VERSION 5.7 ;
  NOWIREEXTENSIONATPIN ON ;
  DIVIDERCHAR "/" ;
  BUSBITCHARS "[]" ;
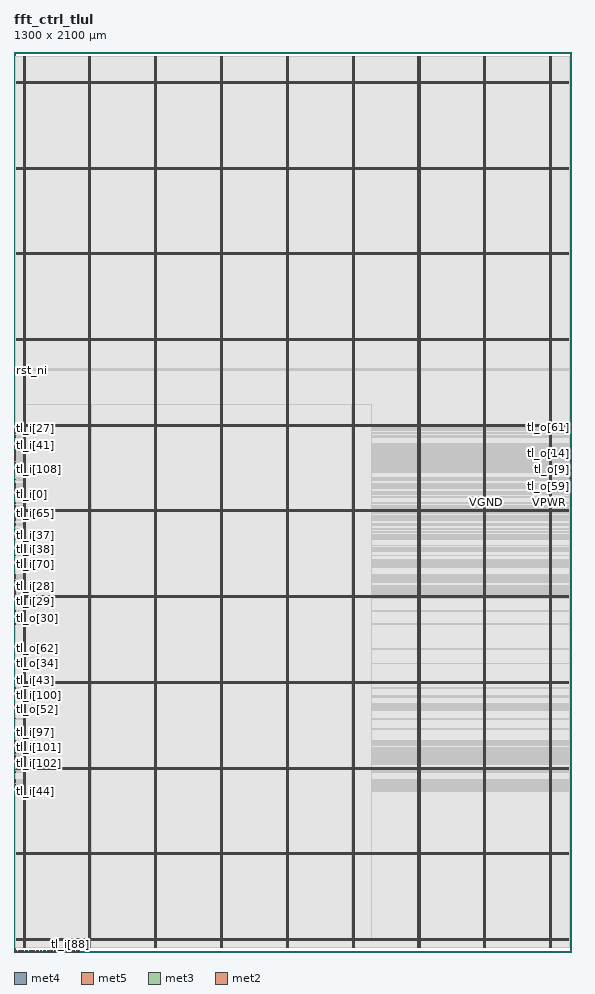
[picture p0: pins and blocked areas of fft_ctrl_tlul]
MACRO fft_ctrl_tlul
  CLASS BLOCK ;
  FOREIGN fft_ctrl_tlul ;
  ORIGIN 0.000 0.000 ;
  SIZE 1300.000 BY 2100.000 ;
  PIN VGND
    DIRECTION INOUT ;
    USE GROUND ;
    PORT
      LAYER met4 ;
        RECT 24.340 10.640 25.940 2089.200 ;
    END
    PORT
      LAYER met4 ;
        RECT 177.940 10.640 179.540 2089.200 ;
    END
    PORT
      LAYER met4 ;
        RECT 331.540 10.640 333.140 2089.200 ;
    END
    PORT
      LAYER met4 ;
        RECT 485.140 10.640 486.740 2089.200 ;
    END
    PORT
      LAYER met4 ;
        RECT 638.740 10.640 640.340 2089.200 ;
    END
    PORT
      LAYER met4 ;
        RECT 792.340 10.640 793.940 2089.200 ;
    END
    PORT
      LAYER met4 ;
        RECT 945.940 10.640 947.540 2089.200 ;
    END
    PORT
      LAYER met4 ;
        RECT 1099.540 10.640 1101.140 2089.200 ;
    END
    PORT
      LAYER met4 ;
        RECT 1253.140 10.640 1254.740 2089.200 ;
    END
    PORT
      LAYER met5 ;
        RECT 5.280 30.030 1294.680 31.630 ;
    END
    PORT
      LAYER met5 ;
        RECT 5.280 230.030 1294.680 231.630 ;
    END
    PORT
      LAYER met5 ;
        RECT 5.280 430.030 1294.680 431.630 ;
    END
    PORT
      LAYER met5 ;
        RECT 5.280 630.030 1294.680 631.630 ;
    END
    PORT
      LAYER met5 ;
        RECT 5.280 830.030 1294.680 831.630 ;
    END
    PORT
      LAYER met5 ;
        RECT 5.280 1030.030 1294.680 1031.630 ;
    END
    PORT
      LAYER met5 ;
        RECT 5.280 1230.030 1294.680 1231.630 ;
    END
    PORT
      LAYER met5 ;
        RECT 5.280 1430.030 1294.680 1431.630 ;
    END
    PORT
      LAYER met5 ;
        RECT 5.280 1630.030 1294.680 1631.630 ;
    END
    PORT
      LAYER met5 ;
        RECT 5.280 1830.030 1294.680 1831.630 ;
    END
    PORT
      LAYER met5 ;
        RECT 5.280 2030.030 1294.680 2031.630 ;
    END
  END VGND
  PIN VPWR
    DIRECTION INOUT ;
    USE POWER ;
    PORT
      LAYER met4 ;
        RECT 21.040 10.640 22.640 2089.200 ;
    END
    PORT
      LAYER met4 ;
        RECT 174.640 10.640 176.240 2089.200 ;
    END
    PORT
      LAYER met4 ;
        RECT 328.240 10.640 329.840 2089.200 ;
    END
    PORT
      LAYER met4 ;
        RECT 481.840 10.640 483.440 2089.200 ;
    END
    PORT
      LAYER met4 ;
        RECT 635.440 10.640 637.040 2089.200 ;
    END
    PORT
      LAYER met4 ;
        RECT 789.040 10.640 790.640 2089.200 ;
    END
    PORT
      LAYER met4 ;
        RECT 942.640 10.640 944.240 2089.200 ;
    END
    PORT
      LAYER met4 ;
        RECT 1096.240 10.640 1097.840 2089.200 ;
    END
    PORT
      LAYER met4 ;
        RECT 1249.840 10.640 1251.440 2089.200 ;
    END
    PORT
      LAYER met5 ;
        RECT 5.280 26.730 1294.680 28.330 ;
    END
    PORT
      LAYER met5 ;
        RECT 5.280 226.730 1294.680 228.330 ;
    END
    PORT
      LAYER met5 ;
        RECT 5.280 426.730 1294.680 428.330 ;
    END
    PORT
      LAYER met5 ;
        RECT 5.280 626.730 1294.680 628.330 ;
    END
    PORT
      LAYER met5 ;
        RECT 5.280 826.730 1294.680 828.330 ;
    END
    PORT
      LAYER met5 ;
        RECT 5.280 1026.730 1294.680 1028.330 ;
    END
    PORT
      LAYER met5 ;
        RECT 5.280 1226.730 1294.680 1228.330 ;
    END
    PORT
      LAYER met5 ;
        RECT 5.280 1426.730 1294.680 1428.330 ;
    END
    PORT
      LAYER met5 ;
        RECT 5.280 1626.730 1294.680 1628.330 ;
    END
    PORT
      LAYER met5 ;
        RECT 5.280 1826.730 1294.680 1828.330 ;
    END
    PORT
      LAYER met5 ;
        RECT 5.280 2026.730 1294.680 2028.330 ;
    END
  END VPWR
  PIN clk_i
    DIRECTION INPUT ;
    USE SIGNAL ;
    ANTENNAGATEAREA 0.929700 ;
    ANTENNADIFFAREA 0.434700 ;
    PORT
      LAYER met3 ;
        RECT 0.000 1360.040 4.000 1360.640 ;
    END
  END clk_i
  PIN fft_done_o
    DIRECTION OUTPUT ;
    USE SIGNAL ;
    ANTENNADIFFAREA 0.445500 ;
    PORT
      LAYER met3 ;
        RECT 0.000 1088.040 4.000 1088.640 ;
    END
  END fft_done_o
  PIN fft_error_o
    DIRECTION OUTPUT ;
    USE SIGNAL ;
    ANTENNADIFFAREA 0.445500 ;
    PORT
      LAYER met3 ;
        RECT 0.000 1060.840 4.000 1061.440 ;
    END
  END fft_error_o
  PIN rst_ni
    DIRECTION INPUT ;
    USE SIGNAL ;
    ANTENNAGATEAREA 0.631200 ;
    ANTENNADIFFAREA 0.434700 ;
    PORT
      LAYER met3 ;
        RECT 0.000 1356.640 4.000 1357.240 ;
    END
  END rst_ni
  PIN tl_i[0]
    DIRECTION INPUT ;
    USE SIGNAL ;
    ANTENNAGATEAREA 0.631200 ;
    ANTENNADIFFAREA 0.434700 ;
    PORT
      LAYER met3 ;
        RECT 0.000 1067.640 4.000 1068.240 ;
    END
  END tl_i[0]
  PIN tl_i[100]
    DIRECTION INPUT ;
    USE SIGNAL ;
    ANTENNAGATEAREA 0.631200 ;
    ANTENNADIFFAREA 0.434700 ;
    PORT
      LAYER met3 ;
        RECT 0.000 598.440 4.000 599.040 ;
    END
  END tl_i[100]
  PIN tl_i[101]
    DIRECTION INPUT ;
    USE SIGNAL ;
    ANTENNAGATEAREA 0.631200 ;
    ANTENNADIFFAREA 0.434700 ;
    PORT
      LAYER met3 ;
        RECT 0.000 476.040 4.000 476.640 ;
    END
  END tl_i[101]
  PIN tl_i[102]
    DIRECTION INPUT ;
    USE SIGNAL ;
    ANTENNAGATEAREA 0.631200 ;
    ANTENNADIFFAREA 0.434700 ;
    PORT
      LAYER met3 ;
        RECT 0.000 459.040 4.000 459.640 ;
    END
  END tl_i[102]
  PIN tl_i[103]
    DIRECTION INPUT ;
    USE SIGNAL ;
    PORT
      LAYER met2 ;
        RECT 0.090 0.000 0.370 4.000 ;
    END
  END tl_i[103]
  PIN tl_i[104]
    DIRECTION INPUT ;
    USE SIGNAL ;
    PORT
      LAYER met2 ;
        RECT 3.310 0.000 3.590 4.000 ;
    END
  END tl_i[104]
  PIN tl_i[105]
    DIRECTION INPUT ;
    USE SIGNAL ;
    PORT
      LAYER met2 ;
        RECT 6.530 0.000 6.810 4.000 ;
    END
  END tl_i[105]
  PIN tl_i[106]
    DIRECTION INPUT ;
    USE SIGNAL ;
    PORT
      LAYER met2 ;
        RECT 9.750 0.000 10.030 4.000 ;
    END
  END tl_i[106]
  PIN tl_i[107]
    DIRECTION INPUT ;
    USE SIGNAL ;
    ANTENNAGATEAREA 0.631200 ;
    ANTENNADIFFAREA 0.434700 ;
    PORT
      LAYER met3 ;
        RECT 0.000 1122.040 4.000 1122.640 ;
    END
  END tl_i[107]
  PIN tl_i[108]
    DIRECTION INPUT ;
    USE SIGNAL ;
    ANTENNAGATEAREA 0.631200 ;
    ANTENNADIFFAREA 0.434700 ;
    PORT
      LAYER met3 ;
        RECT 0.000 1125.440 4.000 1126.040 ;
    END
  END tl_i[108]
  PIN tl_i[109]
    DIRECTION INPUT ;
    USE SIGNAL ;
    ANTENNAGATEAREA 0.631200 ;
    ANTENNADIFFAREA 0.434700 ;
    PORT
      LAYER met3 ;
        RECT 0.000 1074.440 4.000 1075.040 ;
    END
  END tl_i[109]
  PIN tl_i[10]
    DIRECTION INPUT ;
    USE SIGNAL ;
    PORT
      LAYER met2 ;
        RECT 12.970 0.000 13.250 4.000 ;
    END
  END tl_i[10]
  PIN tl_i[11]
    DIRECTION INPUT ;
    USE SIGNAL ;
    PORT
      LAYER met2 ;
        RECT 16.190 0.000 16.470 4.000 ;
    END
  END tl_i[11]
  PIN tl_i[12]
    DIRECTION INPUT ;
    USE SIGNAL ;
    PORT
      LAYER met2 ;
        RECT 19.410 0.000 19.690 4.000 ;
    END
  END tl_i[12]
  PIN tl_i[13]
    DIRECTION INPUT ;
    USE SIGNAL ;
    PORT
      LAYER met2 ;
        RECT 22.630 0.000 22.910 4.000 ;
    END
  END tl_i[13]
  PIN tl_i[14]
    DIRECTION INPUT ;
    USE SIGNAL ;
    PORT
      LAYER met2 ;
        RECT 25.850 0.000 26.130 4.000 ;
    END
  END tl_i[14]
  PIN tl_i[15]
    DIRECTION INPUT ;
    USE SIGNAL ;
    PORT
      LAYER met2 ;
        RECT 29.070 0.000 29.350 4.000 ;
    END
  END tl_i[15]
  PIN tl_i[16]
    DIRECTION INPUT ;
    USE SIGNAL ;
    PORT
      LAYER met2 ;
        RECT 32.290 0.000 32.570 4.000 ;
    END
  END tl_i[16]
  PIN tl_i[17]
    DIRECTION INPUT ;
    USE SIGNAL ;
    PORT
      LAYER met2 ;
        RECT 35.510 0.000 35.790 4.000 ;
    END
  END tl_i[17]
  PIN tl_i[18]
    DIRECTION INPUT ;
    USE SIGNAL ;
    PORT
      LAYER met2 ;
        RECT 38.730 0.000 39.010 4.000 ;
    END
  END tl_i[18]
  PIN tl_i[19]
    DIRECTION INPUT ;
    USE SIGNAL ;
    PORT
      LAYER met2 ;
        RECT 41.950 0.000 42.230 4.000 ;
    END
  END tl_i[19]
  PIN tl_i[1]
    DIRECTION INPUT ;
    USE SIGNAL ;
    PORT
      LAYER met2 ;
        RECT 45.170 0.000 45.450 4.000 ;
    END
  END tl_i[1]
  PIN tl_i[20]
    DIRECTION INPUT ;
    USE SIGNAL ;
    PORT
      LAYER met2 ;
        RECT 48.390 0.000 48.670 4.000 ;
    END
  END tl_i[20]
  PIN tl_i[21]
    DIRECTION INPUT ;
    USE SIGNAL ;
    PORT
      LAYER met2 ;
        RECT 51.610 0.000 51.890 4.000 ;
    END
  END tl_i[21]
  PIN tl_i[22]
    DIRECTION INPUT ;
    USE SIGNAL ;
    PORT
      LAYER met2 ;
        RECT 54.830 0.000 55.110 4.000 ;
    END
  END tl_i[22]
  PIN tl_i[23]
    DIRECTION INPUT ;
    USE SIGNAL ;
    PORT
      LAYER met2 ;
        RECT 58.050 0.000 58.330 4.000 ;
    END
  END tl_i[23]
  PIN tl_i[24]
    DIRECTION INPUT ;
    USE SIGNAL ;
    PORT
      LAYER met2 ;
        RECT 61.270 0.000 61.550 4.000 ;
    END
  END tl_i[24]
  PIN tl_i[25]
    DIRECTION INPUT ;
    USE SIGNAL ;
    ANTENNAGATEAREA 0.631200 ;
    ANTENNADIFFAREA 0.434700 ;
    PORT
      LAYER met3 ;
        RECT 0.000 1162.840 4.000 1163.440 ;
    END
  END tl_i[25]
  PIN tl_i[26]
    DIRECTION INPUT ;
    USE SIGNAL ;
    ANTENNAGATEAREA 0.631200 ;
    ANTENNADIFFAREA 0.434700 ;
    PORT
      LAYER met3 ;
        RECT 0.000 833.040 4.000 833.640 ;
    END
  END tl_i[26]
  PIN tl_i[27]
    DIRECTION INPUT ;
    USE SIGNAL ;
    ANTENNAGATEAREA 0.631200 ;
    ANTENNADIFFAREA 0.434700 ;
    PORT
      LAYER met3 ;
        RECT 0.000 1220.640 4.000 1221.240 ;
    END
  END tl_i[27]
  PIN tl_i[28]
    DIRECTION INPUT ;
    USE SIGNAL ;
    ANTENNAGATEAREA 0.631200 ;
    ANTENNADIFFAREA 0.434700 ;
    PORT
      LAYER met3 ;
        RECT 0.000 853.440 4.000 854.040 ;
    END
  END tl_i[28]
  PIN tl_i[29]
    DIRECTION INPUT ;
    USE SIGNAL ;
    ANTENNAGATEAREA 0.631200 ;
    ANTENNADIFFAREA 0.434700 ;
    PORT
      LAYER met3 ;
        RECT 0.000 836.440 4.000 837.040 ;
    END
  END tl_i[29]
  PIN tl_i[2]
    DIRECTION INPUT ;
    USE SIGNAL ;
    PORT
      LAYER met2 ;
        RECT 64.490 0.000 64.770 4.000 ;
    END
  END tl_i[2]
  PIN tl_i[30]
    DIRECTION INPUT ;
    USE SIGNAL ;
    ANTENNAGATEAREA 0.631200 ;
    ANTENNADIFFAREA 0.434700 ;
    PORT
      LAYER met3 ;
        RECT 0.000 1217.240 4.000 1217.840 ;
    END
  END tl_i[30]
  PIN tl_i[31]
    DIRECTION INPUT ;
    USE SIGNAL ;
    ANTENNAGATEAREA 0.631200 ;
    ANTENNADIFFAREA 0.434700 ;
    PORT
      LAYER met3 ;
        RECT 0.000 1230.840 4.000 1231.440 ;
    END
  END tl_i[31]
  PIN tl_i[32]
    DIRECTION INPUT ;
    USE SIGNAL ;
    ANTENNAGATEAREA 0.631200 ;
    ANTENNADIFFAREA 0.434700 ;
    PORT
      LAYER met3 ;
        RECT 0.000 1227.440 4.000 1228.040 ;
    END
  END tl_i[32]
  PIN tl_i[33]
    DIRECTION INPUT ;
    USE SIGNAL ;
    ANTENNAGATEAREA 0.631200 ;
    ANTENNADIFFAREA 0.434700 ;
    PORT
      LAYER met3 ;
        RECT 0.000 1210.440 4.000 1211.040 ;
    END
  END tl_i[33]
  PIN tl_i[34]
    DIRECTION INPUT ;
    USE SIGNAL ;
    ANTENNAGATEAREA 0.631200 ;
    ANTENNADIFFAREA 0.434700 ;
    PORT
      LAYER met3 ;
        RECT 0.000 914.640 4.000 915.240 ;
    END
  END tl_i[34]
  PIN tl_i[35]
    DIRECTION INPUT ;
    USE SIGNAL ;
    ANTENNAGATEAREA 0.631200 ;
    ANTENNADIFFAREA 0.434700 ;
    PORT
      LAYER met3 ;
        RECT 0.000 1224.040 4.000 1224.640 ;
    END
  END tl_i[35]
  PIN tl_i[36]
    DIRECTION INPUT ;
    USE SIGNAL ;
    ANTENNAGATEAREA 0.631200 ;
    ANTENNADIFFAREA 0.434700 ;
    PORT
      LAYER met3 ;
        RECT 0.000 826.240 4.000 826.840 ;
    END
  END tl_i[36]
  PIN tl_i[37]
    DIRECTION INPUT ;
    USE SIGNAL ;
    ANTENNAGATEAREA 0.631200 ;
    ANTENNADIFFAREA 0.434700 ;
    PORT
      LAYER met3 ;
        RECT 0.000 972.440 4.000 973.040 ;
    END
  END tl_i[37]
  PIN tl_i[38]
    DIRECTION INPUT ;
    USE SIGNAL ;
    ANTENNAGATEAREA 0.631200 ;
    ANTENNADIFFAREA 0.434700 ;
    PORT
      LAYER met3 ;
        RECT 0.000 938.440 4.000 939.040 ;
    END
  END tl_i[38]
  PIN tl_i[39]
    DIRECTION INPUT ;
    USE SIGNAL ;
    ANTENNAGATEAREA 0.631200 ;
    ANTENNADIFFAREA 0.434700 ;
    PORT
      LAYER met3 ;
        RECT 0.000 911.240 4.000 911.840 ;
    END
  END tl_i[39]
  PIN tl_i[3]
    DIRECTION INPUT ;
    USE SIGNAL ;
    PORT
      LAYER met2 ;
        RECT 67.710 0.000 67.990 4.000 ;
    END
  END tl_i[3]
  PIN tl_i[40]
    DIRECTION INPUT ;
    USE SIGNAL ;
    ANTENNAGATEAREA 0.631200 ;
    ANTENNADIFFAREA 0.434700 ;
    PORT
      LAYER met3 ;
        RECT 0.000 1139.040 4.000 1139.640 ;
    END
  END tl_i[40]
  PIN tl_i[41]
    DIRECTION INPUT ;
    USE SIGNAL ;
    ANTENNAGATEAREA 0.631200 ;
    ANTENNADIFFAREA 0.434700 ;
    PORT
      LAYER met3 ;
        RECT 0.000 1200.240 4.000 1200.840 ;
    END
  END tl_i[41]
  PIN tl_i[42]
    DIRECTION INPUT ;
    USE SIGNAL ;
    ANTENNAGATEAREA 0.631200 ;
    ANTENNADIFFAREA 0.434700 ;
    PORT
      LAYER met3 ;
        RECT 0.000 544.040 4.000 544.640 ;
    END
  END tl_i[42]
  PIN tl_i[43]
    DIRECTION INPUT ;
    USE SIGNAL ;
    ANTENNAGATEAREA 0.631200 ;
    ANTENNADIFFAREA 0.434700 ;
    PORT
      LAYER met3 ;
        RECT 0.000 615.440 4.000 616.040 ;
    END
  END tl_i[43]
  PIN tl_i[44]
    DIRECTION INPUT ;
    USE SIGNAL ;
    ANTENNAGATEAREA 0.631200 ;
    ANTENNADIFFAREA 0.434700 ;
    PORT
      LAYER met3 ;
        RECT 0.000 374.040 4.000 374.640 ;
    END
  END tl_i[44]
  PIN tl_i[45]
    DIRECTION INPUT ;
    USE SIGNAL ;
    ANTENNAGATEAREA 0.631200 ;
    ANTENNADIFFAREA 0.434700 ;
    PORT
      LAYER met3 ;
        RECT 0.000 571.240 4.000 571.840 ;
    END
  END tl_i[45]
  PIN tl_i[46]
    DIRECTION INPUT ;
    USE SIGNAL ;
    ANTENNAGATEAREA 0.631200 ;
    ANTENNADIFFAREA 0.434700 ;
    PORT
      LAYER met3 ;
        RECT 0.000 384.240 4.000 384.840 ;
    END
  END tl_i[46]
  PIN tl_i[47]
    DIRECTION INPUT ;
    USE SIGNAL ;
    ANTENNAGATEAREA 0.631200 ;
    ANTENNADIFFAREA 0.434700 ;
    PORT
      LAYER met3 ;
        RECT 0.000 401.240 4.000 401.840 ;
    END
  END tl_i[47]
  PIN tl_i[48]
    DIRECTION INPUT ;
    USE SIGNAL ;
    ANTENNAGATEAREA 0.631200 ;
    ANTENNADIFFAREA 0.434700 ;
    PORT
      LAYER met3 ;
        RECT 0.000 418.240 4.000 418.840 ;
    END
  END tl_i[48]
  PIN tl_i[49]
    DIRECTION INPUT ;
    USE SIGNAL ;
    ANTENNAGATEAREA 0.631200 ;
    ANTENNADIFFAREA 0.434700 ;
    PORT
      LAYER met3 ;
        RECT 0.000 394.440 4.000 395.040 ;
    END
  END tl_i[49]
  PIN tl_i[4]
    DIRECTION INPUT ;
    USE SIGNAL ;
    PORT
      LAYER met2 ;
        RECT 70.930 0.000 71.210 4.000 ;
    END
  END tl_i[4]
  PIN tl_i[50]
    DIRECTION INPUT ;
    USE SIGNAL ;
    ANTENNAGATEAREA 0.631200 ;
    ANTENNADIFFAREA 0.434700 ;
    PORT
      LAYER met3 ;
        RECT 0.000 397.840 4.000 398.440 ;
    END
  END tl_i[50]
  PIN tl_i[51]
    DIRECTION INPUT ;
    USE SIGNAL ;
    ANTENNAGATEAREA 0.631200 ;
    ANTENNADIFFAREA 0.434700 ;
    PORT
      LAYER met3 ;
        RECT 0.000 839.840 4.000 840.440 ;
    END
  END tl_i[51]
  PIN tl_i[52]
    DIRECTION INPUT ;
    USE SIGNAL ;
    ANTENNAGATEAREA 0.631200 ;
    ANTENNADIFFAREA 0.434700 ;
    PORT
      LAYER met3 ;
        RECT 0.000 850.040 4.000 850.640 ;
    END
  END tl_i[52]
  PIN tl_i[53]
    DIRECTION INPUT ;
    USE SIGNAL ;
    ANTENNAGATEAREA 0.631200 ;
    ANTENNADIFFAREA 0.434700 ;
    PORT
      LAYER met3 ;
        RECT 0.000 846.640 4.000 847.240 ;
    END
  END tl_i[53]
  PIN tl_i[54]
    DIRECTION INPUT ;
    USE SIGNAL ;
    ANTENNAGATEAREA 0.631200 ;
    ANTENNADIFFAREA 0.434700 ;
    PORT
      LAYER met3 ;
        RECT 0.000 880.640 4.000 881.240 ;
    END
  END tl_i[54]
  PIN tl_i[55]
    DIRECTION INPUT ;
    USE SIGNAL ;
    ANTENNAGATEAREA 0.631200 ;
    ANTENNADIFFAREA 0.434700 ;
    PORT
      LAYER met3 ;
        RECT 0.000 438.640 4.000 439.240 ;
    END
  END tl_i[55]
  PIN tl_i[56]
    DIRECTION INPUT ;
    USE SIGNAL ;
    ANTENNAGATEAREA 0.631200 ;
    ANTENNADIFFAREA 0.434700 ;
    PORT
      LAYER met3 ;
        RECT 0.000 877.240 4.000 877.840 ;
    END
  END tl_i[56]
  PIN tl_i[57]
    DIRECTION INPUT ;
    USE SIGNAL ;
    PORT
      LAYER met2 ;
        RECT 74.150 0.000 74.430 4.000 ;
    END
  END tl_i[57]
  PIN tl_i[58]
    DIRECTION INPUT ;
    USE SIGNAL ;
    PORT
      LAYER met2 ;
        RECT 77.370 0.000 77.650 4.000 ;
    END
  END tl_i[58]
  PIN tl_i[59]
    DIRECTION INPUT ;
    USE SIGNAL ;
    PORT
      LAYER met2 ;
        RECT 80.590 0.000 80.870 4.000 ;
    END
  END tl_i[59]
  PIN tl_i[5]
    DIRECTION INPUT ;
    USE SIGNAL ;
    PORT
      LAYER met2 ;
        RECT 83.810 0.000 84.090 4.000 ;
    END
  END tl_i[5]
  PIN tl_i[60]
    DIRECTION INPUT ;
    USE SIGNAL ;
    PORT
      LAYER met2 ;
        RECT 87.030 0.000 87.310 4.000 ;
    END
  END tl_i[60]
  PIN tl_i[61]
    DIRECTION INPUT ;
    USE SIGNAL ;
    ANTENNAGATEAREA 0.631200 ;
    ANTENNADIFFAREA 0.434700 ;
    PORT
      LAYER met3 ;
        RECT 0.000 986.040 4.000 986.640 ;
    END
  END tl_i[61]
  PIN tl_i[62]
    DIRECTION INPUT ;
    USE SIGNAL ;
    ANTENNAGATEAREA 0.631200 ;
    ANTENNADIFFAREA 0.434700 ;
    PORT
      LAYER met3 ;
        RECT 0.000 1009.840 4.000 1010.440 ;
    END
  END tl_i[62]
  PIN tl_i[63]
    DIRECTION INPUT ;
    USE SIGNAL ;
    ANTENNAGATEAREA 0.631200 ;
    ANTENNADIFFAREA 0.434700 ;
    PORT
      LAYER met3 ;
        RECT 0.000 935.040 4.000 935.640 ;
    END
  END tl_i[63]
  PIN tl_i[64]
    DIRECTION INPUT ;
    USE SIGNAL ;
    ANTENNAGATEAREA 0.631200 ;
    ANTENNADIFFAREA 0.434700 ;
    PORT
      LAYER met3 ;
        RECT 0.000 996.240 4.000 996.840 ;
    END
  END tl_i[64]
  PIN tl_i[65]
    DIRECTION INPUT ;
    USE SIGNAL ;
    ANTENNAGATEAREA 0.631200 ;
    ANTENNADIFFAREA 0.434700 ;
    PORT
      LAYER met3 ;
        RECT 0.000 1023.440 4.000 1024.040 ;
    END
  END tl_i[65]
  PIN tl_i[66]
    DIRECTION INPUT ;
    USE SIGNAL ;
    ANTENNAGATEAREA 0.631200 ;
    ANTENNADIFFAREA 0.434700 ;
    PORT
      LAYER met3 ;
        RECT 0.000 1030.240 4.000 1030.840 ;
    END
  END tl_i[66]
  PIN tl_i[67]
    DIRECTION INPUT ;
    USE SIGNAL ;
    ANTENNAGATEAREA 0.631200 ;
    ANTENNADIFFAREA 0.434700 ;
    PORT
      LAYER met3 ;
        RECT 0.000 965.640 4.000 966.240 ;
    END
  END tl_i[67]
  PIN tl_i[68]
    DIRECTION INPUT ;
    USE SIGNAL ;
    ANTENNAGATEAREA 0.631200 ;
    ANTENNADIFFAREA 0.434700 ;
    PORT
      LAYER met3 ;
        RECT 0.000 863.640 4.000 864.240 ;
    END
  END tl_i[68]
  PIN tl_i[69]
    DIRECTION INPUT ;
    USE SIGNAL ;
    ANTENNAGATEAREA 0.631200 ;
    ANTENNADIFFAREA 0.434700 ;
    PORT
      LAYER met3 ;
        RECT 0.000 843.240 4.000 843.840 ;
    END
  END tl_i[69]
  PIN tl_i[6]
    DIRECTION INPUT ;
    USE SIGNAL ;
    PORT
      LAYER met2 ;
        RECT 90.250 0.000 90.530 4.000 ;
    END
  END tl_i[6]
  PIN tl_i[70]
    DIRECTION INPUT ;
    USE SIGNAL ;
    ANTENNAGATEAREA 0.631200 ;
    ANTENNADIFFAREA 0.434700 ;
    PORT
      LAYER met3 ;
        RECT 0.000 904.440 4.000 905.040 ;
    END
  END tl_i[70]
  PIN tl_i[71]
    DIRECTION INPUT ;
    USE SIGNAL ;
    ANTENNAGATEAREA 0.631200 ;
    ANTENNADIFFAREA 0.434700 ;
    PORT
      LAYER met3 ;
        RECT 0.000 870.440 4.000 871.040 ;
    END
  END tl_i[71]
  PIN tl_i[72]
    DIRECTION INPUT ;
    USE SIGNAL ;
    ANTENNAGATEAREA 0.631200 ;
    ANTENNADIFFAREA 0.434700 ;
    PORT
      LAYER met3 ;
        RECT 0.000 948.640 4.000 949.240 ;
    END
  END tl_i[72]
  PIN tl_i[73]
    DIRECTION INPUT ;
    USE SIGNAL ;
    ANTENNAGATEAREA 0.631200 ;
    ANTENNADIFFAREA 0.434700 ;
    PORT
      LAYER met3 ;
        RECT 0.000 1145.840 4.000 1146.440 ;
    END
  END tl_i[73]
  PIN tl_i[74]
    DIRECTION INPUT ;
    USE SIGNAL ;
    ANTENNAGATEAREA 0.631200 ;
    ANTENNADIFFAREA 0.434700 ;
    PORT
      LAYER met3 ;
        RECT 0.000 1176.440 4.000 1177.040 ;
    END
  END tl_i[74]
  PIN tl_i[75]
    DIRECTION INPUT ;
    USE SIGNAL ;
    ANTENNAGATEAREA 0.631200 ;
    ANTENNADIFFAREA 0.434700 ;
    PORT
      LAYER met3 ;
        RECT 0.000 1166.240 4.000 1166.840 ;
    END
  END tl_i[75]
  PIN tl_i[76]
    DIRECTION INPUT ;
    USE SIGNAL ;
    ANTENNAGATEAREA 0.631200 ;
    ANTENNADIFFAREA 0.434700 ;
    PORT
      LAYER met3 ;
        RECT 0.000 1152.640 4.000 1153.240 ;
    END
  END tl_i[76]
  PIN tl_i[77]
    DIRECTION INPUT ;
    USE SIGNAL ;
    PORT
      LAYER met2 ;
        RECT 93.470 0.000 93.750 4.000 ;
    END
  END tl_i[77]
  PIN tl_i[78]
    DIRECTION INPUT ;
    USE SIGNAL ;
    PORT
      LAYER met2 ;
        RECT 96.690 0.000 96.970 4.000 ;
    END
  END tl_i[78]
  PIN tl_i[79]
    DIRECTION INPUT ;
    USE SIGNAL ;
    PORT
      LAYER met2 ;
        RECT 99.910 0.000 100.190 4.000 ;
    END
  END tl_i[79]
  PIN tl_i[7]
    DIRECTION INPUT ;
    USE SIGNAL ;
    PORT
      LAYER met2 ;
        RECT 103.130 0.000 103.410 4.000 ;
    END
  END tl_i[7]
  PIN tl_i[80]
    DIRECTION INPUT ;
    USE SIGNAL ;
    PORT
      LAYER met2 ;
        RECT 106.350 0.000 106.630 4.000 ;
    END
  END tl_i[80]
  PIN tl_i[81]
    DIRECTION INPUT ;
    USE SIGNAL ;
    PORT
      LAYER met2 ;
        RECT 109.570 0.000 109.850 4.000 ;
    END
  END tl_i[81]
  PIN tl_i[82]
    DIRECTION INPUT ;
    USE SIGNAL ;
    PORT
      LAYER met2 ;
        RECT 112.790 0.000 113.070 4.000 ;
    END
  END tl_i[82]
  PIN tl_i[83]
    DIRECTION INPUT ;
    USE SIGNAL ;
    PORT
      LAYER met2 ;
        RECT 116.010 0.000 116.290 4.000 ;
    END
  END tl_i[83]
  PIN tl_i[84]
    DIRECTION INPUT ;
    USE SIGNAL ;
    PORT
      LAYER met2 ;
        RECT 119.230 0.000 119.510 4.000 ;
    END
  END tl_i[84]
  PIN tl_i[85]
    DIRECTION INPUT ;
    USE SIGNAL ;
    PORT
      LAYER met2 ;
        RECT 122.450 0.000 122.730 4.000 ;
    END
  END tl_i[85]
  PIN tl_i[86]
    DIRECTION INPUT ;
    USE SIGNAL ;
    PORT
      LAYER met2 ;
        RECT 125.670 0.000 125.950 4.000 ;
    END
  END tl_i[86]
  PIN tl_i[87]
    DIRECTION INPUT ;
    USE SIGNAL ;
    PORT
      LAYER met2 ;
        RECT 128.890 0.000 129.170 4.000 ;
    END
  END tl_i[87]
  PIN tl_i[88]
    DIRECTION INPUT ;
    USE SIGNAL ;
    PORT
      LAYER met2 ;
        RECT 132.110 0.000 132.390 4.000 ;
    END
  END tl_i[88]
  PIN tl_i[89]
    DIRECTION INPUT ;
    USE SIGNAL ;
    PORT
      LAYER met2 ;
        RECT 135.330 0.000 135.610 4.000 ;
    END
  END tl_i[89]
  PIN tl_i[8]
    DIRECTION INPUT ;
    USE SIGNAL ;
    PORT
      LAYER met2 ;
        RECT 138.550 0.000 138.830 4.000 ;
    END
  END tl_i[8]
  PIN tl_i[90]
    DIRECTION INPUT ;
    USE SIGNAL ;
    PORT
      LAYER met2 ;
        RECT 141.770 0.000 142.050 4.000 ;
    END
  END tl_i[90]
  PIN tl_i[91]
    DIRECTION INPUT ;
    USE SIGNAL ;
    PORT
      LAYER met2 ;
        RECT 144.990 0.000 145.270 4.000 ;
    END
  END tl_i[91]
  PIN tl_i[92]
    DIRECTION INPUT ;
    USE SIGNAL ;
    PORT
      LAYER met2 ;
        RECT 148.210 0.000 148.490 4.000 ;
    END
  END tl_i[92]
  PIN tl_i[93]
    DIRECTION INPUT ;
    USE SIGNAL ;
    ANTENNAGATEAREA 0.631200 ;
    ANTENNADIFFAREA 0.434700 ;
    PORT
      LAYER met3 ;
        RECT 0.000 380.840 4.000 381.440 ;
    END
  END tl_i[93]
  PIN tl_i[94]
    DIRECTION INPUT ;
    USE SIGNAL ;
    ANTENNAGATEAREA 0.631200 ;
    ANTENNADIFFAREA 0.434700 ;
    PORT
      LAYER met3 ;
        RECT 0.000 391.040 4.000 391.640 ;
    END
  END tl_i[94]
  PIN tl_i[95]
    DIRECTION INPUT ;
    USE SIGNAL ;
    ANTENNAGATEAREA 0.631200 ;
    ANTENNADIFFAREA 0.434700 ;
    PORT
      LAYER met3 ;
        RECT 0.000 425.040 4.000 425.640 ;
    END
  END tl_i[95]
  PIN tl_i[96]
    DIRECTION INPUT ;
    USE SIGNAL ;
    ANTENNAGATEAREA 0.631200 ;
    ANTENNADIFFAREA 0.434700 ;
    PORT
      LAYER met3 ;
        RECT 0.000 567.840 4.000 568.440 ;
    END
  END tl_i[96]
  PIN tl_i[97]
    DIRECTION INPUT ;
    USE SIGNAL ;
    ANTENNAGATEAREA 0.631200 ;
    ANTENNADIFFAREA 0.434700 ;
    PORT
      LAYER met3 ;
        RECT 0.000 493.040 4.000 493.640 ;
    END
  END tl_i[97]
  PIN tl_i[98]
    DIRECTION INPUT ;
    USE SIGNAL ;
    ANTENNAGATEAREA 0.631200 ;
    ANTENNADIFFAREA 0.434700 ;
    PORT
      LAYER met3 ;
        RECT 0.000 578.040 4.000 578.640 ;
    END
  END tl_i[98]
  PIN tl_i[99]
    DIRECTION INPUT ;
    USE SIGNAL ;
    ANTENNAGATEAREA 0.631200 ;
    ANTENNADIFFAREA 0.434700 ;
    PORT
      LAYER met3 ;
        RECT 0.000 486.240 4.000 486.840 ;
    END
  END tl_i[99]
  PIN tl_i[9]
    DIRECTION INPUT ;
    USE SIGNAL ;
    PORT
      LAYER met2 ;
        RECT 151.430 0.000 151.710 4.000 ;
    END
  END tl_i[9]
  PIN tl_o[0]
    DIRECTION OUTPUT ;
    USE SIGNAL ;
    ANTENNADIFFAREA 0.445500 ;
    PORT
      LAYER met3 ;
        RECT 0.000 1033.640 4.000 1034.240 ;
    END
  END tl_o[0]
  PIN tl_o[10]
    DIRECTION OUTPUT ;
    USE SIGNAL ;
    PORT
      LAYER met3 ;
        RECT 0.000 1081.240 4.000 1081.840 ;
    END
  END tl_o[10]
  PIN tl_o[11]
    DIRECTION OUTPUT ;
    USE SIGNAL ;
    PORT
      LAYER met3 ;
        RECT 0.000 1128.840 4.000 1129.440 ;
    END
  END tl_o[11]
  PIN tl_o[12]
    DIRECTION OUTPUT ;
    USE SIGNAL ;
    PORT
      LAYER met3 ;
        RECT 0.000 1047.240 4.000 1047.840 ;
    END
  END tl_o[12]
  PIN tl_o[13]
    DIRECTION OUTPUT ;
    USE SIGNAL ;
    PORT
      LAYER met3 ;
        RECT 0.000 1135.640 4.000 1136.240 ;
    END
  END tl_o[13]
  PIN tl_o[14]
    DIRECTION OUTPUT ;
    USE SIGNAL ;
    PORT
      LAYER met3 ;
        RECT 1296.000 1162.840 1300.000 1163.440 ;
    END
  END tl_o[14]
  PIN tl_o[15]
    DIRECTION OUTPUT ;
    USE SIGNAL ;
    PORT
      LAYER met3 ;
        RECT 1296.000 1122.040 1300.000 1122.640 ;
    END
  END tl_o[15]
  PIN tl_o[16]
    DIRECTION OUTPUT ;
    USE SIGNAL ;
    ANTENNADIFFAREA 0.445500 ;
    PORT
      LAYER met3 ;
        RECT 0.000 1132.240 4.000 1132.840 ;
    END
  END tl_o[16]
  PIN tl_o[17]
    DIRECTION OUTPUT ;
    USE SIGNAL ;
    ANTENNADIFFAREA 0.445500 ;
    PORT
      LAYER met3 ;
        RECT 0.000 999.640 4.000 1000.240 ;
    END
  END tl_o[17]
  PIN tl_o[18]
    DIRECTION OUTPUT ;
    USE SIGNAL ;
    ANTENNADIFFAREA 0.445500 ;
    PORT
      LAYER met3 ;
        RECT 0.000 1173.040 4.000 1173.640 ;
    END
  END tl_o[18]
  PIN tl_o[19]
    DIRECTION OUTPUT ;
    USE SIGNAL ;
    ANTENNADIFFAREA 0.445500 ;
    PORT
      LAYER met3 ;
        RECT 0.000 941.840 4.000 942.440 ;
    END
  END tl_o[19]
  PIN tl_o[1]
    DIRECTION OUTPUT ;
    USE SIGNAL ;
    PORT
      LAYER met3 ;
        RECT 0.000 1084.640 4.000 1085.240 ;
    END
  END tl_o[1]
  PIN tl_o[20]
    DIRECTION OUTPUT ;
    USE SIGNAL ;
    ANTENNADIFFAREA 0.445500 ;
    PORT
      LAYER met3 ;
        RECT 0.000 907.840 4.000 908.440 ;
    END
  END tl_o[20]
  PIN tl_o[21]
    DIRECTION OUTPUT ;
    USE SIGNAL ;
    ANTENNADIFFAREA 0.445500 ;
    PORT
      LAYER met3 ;
        RECT 0.000 1101.640 4.000 1102.240 ;
    END
  END tl_o[21]
  PIN tl_o[22]
    DIRECTION OUTPUT ;
    USE SIGNAL ;
    ANTENNADIFFAREA 0.445500 ;
    PORT
      LAYER met3 ;
        RECT 0.000 1156.040 4.000 1156.640 ;
    END
  END tl_o[22]
  PIN tl_o[23]
    DIRECTION OUTPUT ;
    USE SIGNAL ;
    ANTENNADIFFAREA 0.445500 ;
    PORT
      LAYER met3 ;
        RECT 0.000 1179.840 4.000 1180.440 ;
    END
  END tl_o[23]
  PIN tl_o[24]
    DIRECTION OUTPUT ;
    USE SIGNAL ;
    ANTENNADIFFAREA 0.445500 ;
    PORT
      LAYER met3 ;
        RECT 0.000 1186.640 4.000 1187.240 ;
    END
  END tl_o[24]
  PIN tl_o[25]
    DIRECTION OUTPUT ;
    USE SIGNAL ;
    ANTENNADIFFAREA 0.445500 ;
    PORT
      LAYER met3 ;
        RECT 0.000 979.240 4.000 979.840 ;
    END
  END tl_o[25]
  PIN tl_o[26]
    DIRECTION OUTPUT ;
    USE SIGNAL ;
    ANTENNADIFFAREA 0.445500 ;
    PORT
      LAYER met3 ;
        RECT 0.000 1183.240 4.000 1183.840 ;
    END
  END tl_o[26]
  PIN tl_o[27]
    DIRECTION OUTPUT ;
    USE SIGNAL ;
    ANTENNADIFFAREA 0.445500 ;
    PORT
      LAYER met3 ;
        RECT 0.000 1071.040 4.000 1071.640 ;
    END
  END tl_o[27]
  PIN tl_o[28]
    DIRECTION OUTPUT ;
    USE SIGNAL ;
    ANTENNADIFFAREA 0.445500 ;
    PORT
      LAYER met3 ;
        RECT 0.000 1016.640 4.000 1017.240 ;
    END
  END tl_o[28]
  PIN tl_o[29]
    DIRECTION OUTPUT ;
    USE SIGNAL ;
    ANTENNADIFFAREA 0.445500 ;
    PORT
      LAYER met3 ;
        RECT 0.000 1037.040 4.000 1037.640 ;
    END
  END tl_o[29]
  PIN tl_o[2]
    DIRECTION OUTPUT ;
    USE SIGNAL ;
    PORT
      LAYER met3 ;
        RECT 0.000 1142.440 4.000 1143.040 ;
    END
  END tl_o[2]
  PIN tl_o[30]
    DIRECTION OUTPUT ;
    USE SIGNAL ;
    ANTENNADIFFAREA 0.445500 ;
    PORT
      LAYER met3 ;
        RECT 0.000 795.640 4.000 796.240 ;
    END
  END tl_o[30]
  PIN tl_o[31]
    DIRECTION OUTPUT ;
    USE SIGNAL ;
    ANTENNADIFFAREA 0.445500 ;
    PORT
      LAYER met3 ;
        RECT 0.000 1118.640 4.000 1119.240 ;
    END
  END tl_o[31]
  PIN tl_o[32]
    DIRECTION OUTPUT ;
    USE SIGNAL ;
    ANTENNADIFFAREA 0.445500 ;
    PORT
      LAYER met3 ;
        RECT 0.000 1149.240 4.000 1149.840 ;
    END
  END tl_o[32]
  PIN tl_o[33]
    DIRECTION OUTPUT ;
    USE SIGNAL ;
    ANTENNADIFFAREA 0.445500 ;
    PORT
      LAYER met3 ;
        RECT 0.000 520.240 4.000 520.840 ;
    END
  END tl_o[33]
  PIN tl_o[34]
    DIRECTION OUTPUT ;
    USE SIGNAL ;
    ANTENNADIFFAREA 0.445500 ;
    PORT
      LAYER met3 ;
        RECT 0.000 673.240 4.000 673.840 ;
    END
  END tl_o[34]
  PIN tl_o[35]
    DIRECTION OUTPUT ;
    USE SIGNAL ;
    ANTENNADIFFAREA 0.445500 ;
    PORT
      LAYER met3 ;
        RECT 0.000 455.640 4.000 456.240 ;
    END
  END tl_o[35]
  PIN tl_o[36]
    DIRECTION OUTPUT ;
    USE SIGNAL ;
    ANTENNADIFFAREA 0.445500 ;
    PORT
      LAYER met3 ;
        RECT 0.000 765.040 4.000 765.640 ;
    END
  END tl_o[36]
  PIN tl_o[37]
    DIRECTION OUTPUT ;
    USE SIGNAL ;
    ANTENNADIFFAREA 0.445500 ;
    PORT
      LAYER met3 ;
        RECT 0.000 442.040 4.000 442.640 ;
    END
  END tl_o[37]
  PIN tl_o[38]
    DIRECTION OUTPUT ;
    USE SIGNAL ;
    ANTENNADIFFAREA 0.445500 ;
    PORT
      LAYER met3 ;
        RECT 0.000 445.440 4.000 446.040 ;
    END
  END tl_o[38]
  PIN tl_o[39]
    DIRECTION OUTPUT ;
    USE SIGNAL ;
    ANTENNADIFFAREA 0.445500 ;
    PORT
      LAYER met3 ;
        RECT 0.000 452.240 4.000 452.840 ;
    END
  END tl_o[39]
  PIN tl_o[3]
    DIRECTION OUTPUT ;
    USE SIGNAL ;
    PORT
      LAYER met3 ;
        RECT 0.000 969.040 4.000 969.640 ;
    END
  END tl_o[3]
  PIN tl_o[40]
    DIRECTION OUTPUT ;
    USE SIGNAL ;
    ANTENNADIFFAREA 0.445500 ;
    PORT
      LAYER met3 ;
        RECT 0.000 469.240 4.000 469.840 ;
    END
  END tl_o[40]
  PIN tl_o[41]
    DIRECTION OUTPUT ;
    USE SIGNAL ;
    ANTENNADIFFAREA 0.445500 ;
    PORT
      LAYER met3 ;
        RECT 0.000 465.840 4.000 466.440 ;
    END
  END tl_o[41]
  PIN tl_o[42]
    DIRECTION OUTPUT ;
    USE SIGNAL ;
    ANTENNADIFFAREA 0.445500 ;
    PORT
      LAYER met3 ;
        RECT 0.000 867.040 4.000 867.640 ;
    END
  END tl_o[42]
  PIN tl_o[43]
    DIRECTION OUTPUT ;
    USE SIGNAL ;
    ANTENNADIFFAREA 0.445500 ;
    PORT
      LAYER met3 ;
        RECT 0.000 873.840 4.000 874.440 ;
    END
  END tl_o[43]
  PIN tl_o[44]
    DIRECTION OUTPUT ;
    USE SIGNAL ;
    ANTENNADIFFAREA 0.445500 ;
    PORT
      LAYER met3 ;
        RECT 0.000 897.640 4.000 898.240 ;
    END
  END tl_o[44]
  PIN tl_o[45]
    DIRECTION OUTPUT ;
    USE SIGNAL ;
    ANTENNADIFFAREA 0.445500 ;
    PORT
      LAYER met3 ;
        RECT 0.000 901.040 4.000 901.640 ;
    END
  END tl_o[45]
  PIN tl_o[46]
    DIRECTION OUTPUT ;
    USE SIGNAL ;
    ANTENNADIFFAREA 0.445500 ;
    PORT
      LAYER met3 ;
        RECT 0.000 448.840 4.000 449.440 ;
    END
  END tl_o[46]
  PIN tl_o[47]
    DIRECTION OUTPUT ;
    USE SIGNAL ;
    ANTENNADIFFAREA 0.445500 ;
    PORT
      LAYER met3 ;
        RECT 0.000 829.640 4.000 830.240 ;
    END
  END tl_o[47]
  PIN tl_o[48]
    DIRECTION OUTPUT ;
    USE SIGNAL ;
    PORT
      LAYER met3 ;
        RECT 0.000 1203.640 4.000 1204.240 ;
    END
  END tl_o[48]
  PIN tl_o[49]
    DIRECTION OUTPUT ;
    USE SIGNAL ;
    ANTENNADIFFAREA 0.445500 ;
    PORT
      LAYER met3 ;
        RECT 0.000 377.440 4.000 378.040 ;
    END
  END tl_o[49]
  PIN tl_o[4]
    DIRECTION OUTPUT ;
    USE SIGNAL ;
    PORT
      LAYER met3 ;
        RECT 0.000 924.840 4.000 925.440 ;
    END
  END tl_o[4]
  PIN tl_o[50]
    DIRECTION OUTPUT ;
    USE SIGNAL ;
    ANTENNADIFFAREA 0.445500 ;
    PORT
      LAYER met3 ;
        RECT 0.000 387.640 4.000 388.240 ;
    END
  END tl_o[50]
  PIN tl_o[51]
    DIRECTION OUTPUT ;
    USE SIGNAL ;
    ANTENNADIFFAREA 0.445500 ;
    PORT
      LAYER met3 ;
        RECT 0.000 421.640 4.000 422.240 ;
    END
  END tl_o[51]
  PIN tl_o[52]
    DIRECTION OUTPUT ;
    USE SIGNAL ;
    ANTENNADIFFAREA 0.445500 ;
    PORT
      LAYER met3 ;
        RECT 0.000 564.440 4.000 565.040 ;
    END
  END tl_o[52]
  PIN tl_o[53]
    DIRECTION OUTPUT ;
    USE SIGNAL ;
    ANTENNADIFFAREA 0.445500 ;
    PORT
      LAYER met3 ;
        RECT 0.000 489.640 4.000 490.240 ;
    END
  END tl_o[53]
  PIN tl_o[54]
    DIRECTION OUTPUT ;
    USE SIGNAL ;
    ANTENNADIFFAREA 0.445500 ;
    PORT
      LAYER met3 ;
        RECT 0.000 574.640 4.000 575.240 ;
    END
  END tl_o[54]
  PIN tl_o[55]
    DIRECTION OUTPUT ;
    USE SIGNAL ;
    ANTENNADIFFAREA 0.445500 ;
    PORT
      LAYER met3 ;
        RECT 0.000 482.840 4.000 483.440 ;
    END
  END tl_o[55]
  PIN tl_o[56]
    DIRECTION OUTPUT ;
    USE SIGNAL ;
    ANTENNADIFFAREA 0.445500 ;
    PORT
      LAYER met3 ;
        RECT 0.000 595.040 4.000 595.640 ;
    END
  END tl_o[56]
  PIN tl_o[57]
    DIRECTION OUTPUT ;
    USE SIGNAL ;
    ANTENNADIFFAREA 0.445500 ;
    PORT
      LAYER met3 ;
        RECT 0.000 462.440 4.000 463.040 ;
    END
  END tl_o[57]
  PIN tl_o[58]
    DIRECTION OUTPUT ;
    USE SIGNAL ;
    ANTENNADIFFAREA 0.445500 ;
    PORT
      LAYER met3 ;
        RECT 0.000 472.640 4.000 473.240 ;
    END
  END tl_o[58]
  PIN tl_o[59]
    DIRECTION OUTPUT ;
    USE SIGNAL ;
    PORT
      LAYER met3 ;
        RECT 1296.000 1105.040 1300.000 1105.640 ;
    END
  END tl_o[59]
  PIN tl_o[5]
    DIRECTION OUTPUT ;
    USE SIGNAL ;
    PORT
      LAYER met3 ;
        RECT 0.000 1169.640 4.000 1170.240 ;
    END
  END tl_o[5]
  PIN tl_o[60]
    DIRECTION OUTPUT ;
    USE SIGNAL ;
    PORT
      LAYER met3 ;
        RECT 0.000 1159.440 4.000 1160.040 ;
    END
  END tl_o[60]
  PIN tl_o[61]
    DIRECTION OUTPUT ;
    USE SIGNAL ;
    PORT
      LAYER met3 ;
        RECT 1296.000 1224.040 1300.000 1224.640 ;
    END
  END tl_o[61]
  PIN tl_o[62]
    DIRECTION OUTPUT ;
    USE SIGNAL ;
    ANTENNADIFFAREA 0.445500 ;
    PORT
      LAYER met3 ;
        RECT 0.000 707.240 4.000 707.840 ;
    END
  END tl_o[62]
  PIN tl_o[63]
    DIRECTION OUTPUT ;
    USE SIGNAL ;
    PORT
      LAYER met3 ;
        RECT 1296.000 1145.840 1300.000 1146.440 ;
    END
  END tl_o[63]
  PIN tl_o[64]
    DIRECTION OUTPUT ;
    USE SIGNAL ;
    PORT
      LAYER met3 ;
        RECT 0.000 962.240 4.000 962.840 ;
    END
  END tl_o[64]
  PIN tl_o[65]
    DIRECTION OUTPUT ;
    USE SIGNAL ;
    ANTENNADIFFAREA 0.445500 ;
    PORT
      LAYER met3 ;
        RECT 0.000 1040.440 4.000 1041.040 ;
    END
  END tl_o[65]
  PIN tl_o[6]
    DIRECTION OUTPUT ;
    USE SIGNAL ;
    PORT
      LAYER met3 ;
        RECT 0.000 1091.440 4.000 1092.040 ;
    END
  END tl_o[6]
  PIN tl_o[7]
    DIRECTION OUTPUT ;
    USE SIGNAL ;
    PORT
      LAYER met3 ;
        RECT 0.000 1006.440 4.000 1007.040 ;
    END
  END tl_o[7]
  PIN tl_o[8]
    DIRECTION OUTPUT ;
    USE SIGNAL ;
    PORT
      LAYER met3 ;
        RECT 0.000 1013.240 4.000 1013.840 ;
    END
  END tl_o[8]
  PIN tl_o[9]
    DIRECTION OUTPUT ;
    USE SIGNAL ;
    PORT
      LAYER met3 ;
        RECT 1296.000 1125.440 1300.000 1126.040 ;
    END
  END tl_o[9]
  OBS
      LAYER nwell ;
        RECT 5.330 10.795 1294.630 2089.045 ;
      LAYER li1 ;
        RECT 5.520 10.795 1294.440 2089.045 ;
      LAYER met1 ;
        RECT 4.210 10.640 1294.440 2089.200 ;
      LAYER met2 ;
        RECT 4.230 10.695 1292.510 2089.145 ;
      LAYER met3 ;
        RECT 3.990 1361.040 1296.000 2089.125 ;
        RECT 4.400 1359.640 1296.000 1361.040 ;
        RECT 3.990 1357.640 1296.000 1359.640 ;
        RECT 4.400 1356.240 1296.000 1357.640 ;
        RECT 3.990 1231.840 1296.000 1356.240 ;
        RECT 4.400 1230.440 1296.000 1231.840 ;
        RECT 3.990 1228.440 1296.000 1230.440 ;
        RECT 4.400 1227.040 1296.000 1228.440 ;
        RECT 3.990 1225.040 1296.000 1227.040 ;
        RECT 4.400 1223.640 1295.600 1225.040 ;
        RECT 3.990 1221.640 1296.000 1223.640 ;
        RECT 4.400 1220.240 1296.000 1221.640 ;
        RECT 3.990 1218.240 1296.000 1220.240 ;
        RECT 4.400 1216.840 1296.000 1218.240 ;
        RECT 3.990 1211.440 1296.000 1216.840 ;
        RECT 4.400 1210.040 1296.000 1211.440 ;
        RECT 3.990 1204.640 1296.000 1210.040 ;
        RECT 4.400 1203.240 1296.000 1204.640 ;
        RECT 3.990 1201.240 1296.000 1203.240 ;
        RECT 4.400 1199.840 1296.000 1201.240 ;
        RECT 3.990 1187.640 1296.000 1199.840 ;
        RECT 4.400 1186.240 1296.000 1187.640 ;
        RECT 3.990 1184.240 1296.000 1186.240 ;
        RECT 4.400 1182.840 1296.000 1184.240 ;
        RECT 3.990 1180.840 1296.000 1182.840 ;
        RECT 4.400 1179.440 1296.000 1180.840 ;
        RECT 3.990 1177.440 1296.000 1179.440 ;
        RECT 4.400 1176.040 1296.000 1177.440 ;
        RECT 3.990 1174.040 1296.000 1176.040 ;
        RECT 4.400 1172.640 1296.000 1174.040 ;
        RECT 3.990 1170.640 1296.000 1172.640 ;
        RECT 4.400 1169.240 1296.000 1170.640 ;
        RECT 3.990 1167.240 1296.000 1169.240 ;
        RECT 4.400 1165.840 1296.000 1167.240 ;
        RECT 3.990 1163.840 1296.000 1165.840 ;
        RECT 4.400 1162.440 1295.600 1163.840 ;
        RECT 3.990 1160.440 1296.000 1162.440 ;
        RECT 4.400 1159.040 1296.000 1160.440 ;
        RECT 3.990 1157.040 1296.000 1159.040 ;
        RECT 4.400 1155.640 1296.000 1157.040 ;
        RECT 3.990 1153.640 1296.000 1155.640 ;
        RECT 4.400 1152.240 1296.000 1153.640 ;
        RECT 3.990 1150.240 1296.000 1152.240 ;
        RECT 4.400 1148.840 1296.000 1150.240 ;
        RECT 3.990 1146.840 1296.000 1148.840 ;
        RECT 4.400 1145.440 1295.600 1146.840 ;
        RECT 3.990 1143.440 1296.000 1145.440 ;
        RECT 4.400 1142.040 1296.000 1143.440 ;
        RECT 3.990 1140.040 1296.000 1142.040 ;
        RECT 4.400 1138.640 1296.000 1140.040 ;
        RECT 3.990 1136.640 1296.000 1138.640 ;
        RECT 4.400 1135.240 1296.000 1136.640 ;
        RECT 3.990 1133.240 1296.000 1135.240 ;
        RECT 4.400 1131.840 1296.000 1133.240 ;
        RECT 3.990 1129.840 1296.000 1131.840 ;
        RECT 4.400 1128.440 1296.000 1129.840 ;
        RECT 3.990 1126.440 1296.000 1128.440 ;
        RECT 4.400 1125.040 1295.600 1126.440 ;
        RECT 3.990 1123.040 1296.000 1125.040 ;
        RECT 4.400 1121.640 1295.600 1123.040 ;
        RECT 3.990 1119.640 1296.000 1121.640 ;
        RECT 4.400 1118.240 1296.000 1119.640 ;
        RECT 3.990 1106.040 1296.000 1118.240 ;
        RECT 3.990 1104.640 1295.600 1106.040 ;
        RECT 3.990 1102.640 1296.000 1104.640 ;
        RECT 4.400 1101.240 1296.000 1102.640 ;
        RECT 3.990 1092.440 1296.000 1101.240 ;
        RECT 4.400 1091.040 1296.000 1092.440 ;
        RECT 3.990 1089.040 1296.000 1091.040 ;
        RECT 4.400 1087.640 1296.000 1089.040 ;
        RECT 3.990 1085.640 1296.000 1087.640 ;
        RECT 4.400 1084.240 1296.000 1085.640 ;
        RECT 3.990 1082.240 1296.000 1084.240 ;
        RECT 4.400 1080.840 1296.000 1082.240 ;
        RECT 3.990 1075.440 1296.000 1080.840 ;
        RECT 4.400 1074.040 1296.000 1075.440 ;
        RECT 3.990 1072.040 1296.000 1074.040 ;
        RECT 4.400 1070.640 1296.000 1072.040 ;
        RECT 3.990 1068.640 1296.000 1070.640 ;
        RECT 4.400 1067.240 1296.000 1068.640 ;
        RECT 3.990 1061.840 1296.000 1067.240 ;
        RECT 4.400 1060.440 1296.000 1061.840 ;
        RECT 3.990 1048.240 1296.000 1060.440 ;
        RECT 4.400 1046.840 1296.000 1048.240 ;
        RECT 3.990 1041.440 1296.000 1046.840 ;
        RECT 4.400 1040.040 1296.000 1041.440 ;
        RECT 3.990 1038.040 1296.000 1040.040 ;
        RECT 4.400 1036.640 1296.000 1038.040 ;
        RECT 3.990 1034.640 1296.000 1036.640 ;
        RECT 4.400 1033.240 1296.000 1034.640 ;
        RECT 3.990 1031.240 1296.000 1033.240 ;
        RECT 4.400 1029.840 1296.000 1031.240 ;
        RECT 3.990 1024.440 1296.000 1029.840 ;
        RECT 4.400 1023.040 1296.000 1024.440 ;
        RECT 3.990 1017.640 1296.000 1023.040 ;
        RECT 4.400 1016.240 1296.000 1017.640 ;
        RECT 3.990 1014.240 1296.000 1016.240 ;
        RECT 4.400 1012.840 1296.000 1014.240 ;
        RECT 3.990 1010.840 1296.000 1012.840 ;
        RECT 4.400 1009.440 1296.000 1010.840 ;
        RECT 3.990 1007.440 1296.000 1009.440 ;
        RECT 4.400 1006.040 1296.000 1007.440 ;
        RECT 3.990 1000.640 1296.000 1006.040 ;
        RECT 4.400 999.240 1296.000 1000.640 ;
        RECT 3.990 997.240 1296.000 999.240 ;
        RECT 4.400 995.840 1296.000 997.240 ;
        RECT 3.990 987.040 1296.000 995.840 ;
        RECT 4.400 985.640 1296.000 987.040 ;
        RECT 3.990 980.240 1296.000 985.640 ;
        RECT 4.400 978.840 1296.000 980.240 ;
        RECT 3.990 973.440 1296.000 978.840 ;
        RECT 4.400 972.040 1296.000 973.440 ;
        RECT 3.990 970.040 1296.000 972.040 ;
        RECT 4.400 968.640 1296.000 970.040 ;
        RECT 3.990 966.640 1296.000 968.640 ;
        RECT 4.400 965.240 1296.000 966.640 ;
        RECT 3.990 963.240 1296.000 965.240 ;
        RECT 4.400 961.840 1296.000 963.240 ;
        RECT 3.990 949.640 1296.000 961.840 ;
        RECT 4.400 948.240 1296.000 949.640 ;
        RECT 3.990 942.840 1296.000 948.240 ;
        RECT 4.400 941.440 1296.000 942.840 ;
        RECT 3.990 939.440 1296.000 941.440 ;
        RECT 4.400 938.040 1296.000 939.440 ;
        RECT 3.990 936.040 1296.000 938.040 ;
        RECT 4.400 934.640 1296.000 936.040 ;
        RECT 3.990 925.840 1296.000 934.640 ;
        RECT 4.400 924.440 1296.000 925.840 ;
        RECT 3.990 915.640 1296.000 924.440 ;
        RECT 4.400 914.240 1296.000 915.640 ;
        RECT 3.990 912.240 1296.000 914.240 ;
        RECT 4.400 910.840 1296.000 912.240 ;
        RECT 3.990 908.840 1296.000 910.840 ;
        RECT 4.400 907.440 1296.000 908.840 ;
        RECT 3.990 905.440 1296.000 907.440 ;
        RECT 4.400 904.040 1296.000 905.440 ;
        RECT 3.990 902.040 1296.000 904.040 ;
        RECT 4.400 900.640 1296.000 902.040 ;
        RECT 3.990 898.640 1296.000 900.640 ;
        RECT 4.400 897.240 1296.000 898.640 ;
        RECT 3.990 881.640 1296.000 897.240 ;
        RECT 4.400 880.240 1296.000 881.640 ;
        RECT 3.990 878.240 1296.000 880.240 ;
        RECT 4.400 876.840 1296.000 878.240 ;
        RECT 3.990 874.840 1296.000 876.840 ;
        RECT 4.400 873.440 1296.000 874.840 ;
        RECT 3.990 871.440 1296.000 873.440 ;
        RECT 4.400 870.040 1296.000 871.440 ;
        RECT 3.990 868.040 1296.000 870.040 ;
        RECT 4.400 866.640 1296.000 868.040 ;
        RECT 3.990 864.640 1296.000 866.640 ;
        RECT 4.400 863.240 1296.000 864.640 ;
        RECT 3.990 854.440 1296.000 863.240 ;
        RECT 4.400 853.040 1296.000 854.440 ;
        RECT 3.990 851.040 1296.000 853.040 ;
        RECT 4.400 849.640 1296.000 851.040 ;
        RECT 3.990 847.640 1296.000 849.640 ;
        RECT 4.400 846.240 1296.000 847.640 ;
        RECT 3.990 844.240 1296.000 846.240 ;
        RECT 4.400 842.840 1296.000 844.240 ;
        RECT 3.990 840.840 1296.000 842.840 ;
        RECT 4.400 839.440 1296.000 840.840 ;
        RECT 3.990 837.440 1296.000 839.440 ;
        RECT 4.400 836.040 1296.000 837.440 ;
        RECT 3.990 834.040 1296.000 836.040 ;
        RECT 4.400 832.640 1296.000 834.040 ;
        RECT 3.990 830.640 1296.000 832.640 ;
        RECT 4.400 829.240 1296.000 830.640 ;
        RECT 3.990 827.240 1296.000 829.240 ;
        RECT 4.400 825.840 1296.000 827.240 ;
        RECT 3.990 796.640 1296.000 825.840 ;
        RECT 4.400 795.240 1296.000 796.640 ;
        RECT 3.990 766.040 1296.000 795.240 ;
        RECT 4.400 764.640 1296.000 766.040 ;
        RECT 3.990 708.240 1296.000 764.640 ;
        RECT 4.400 706.840 1296.000 708.240 ;
        RECT 3.990 674.240 1296.000 706.840 ;
        RECT 4.400 672.840 1296.000 674.240 ;
        RECT 3.990 616.440 1296.000 672.840 ;
        RECT 4.400 615.040 1296.000 616.440 ;
        RECT 3.990 599.440 1296.000 615.040 ;
        RECT 4.400 598.040 1296.000 599.440 ;
        RECT 3.990 596.040 1296.000 598.040 ;
        RECT 4.400 594.640 1296.000 596.040 ;
        RECT 3.990 579.040 1296.000 594.640 ;
        RECT 4.400 577.640 1296.000 579.040 ;
        RECT 3.990 575.640 1296.000 577.640 ;
        RECT 4.400 574.240 1296.000 575.640 ;
        RECT 3.990 572.240 1296.000 574.240 ;
        RECT 4.400 570.840 1296.000 572.240 ;
        RECT 3.990 568.840 1296.000 570.840 ;
        RECT 4.400 567.440 1296.000 568.840 ;
        RECT 3.990 565.440 1296.000 567.440 ;
        RECT 4.400 564.040 1296.000 565.440 ;
        RECT 3.990 545.040 1296.000 564.040 ;
        RECT 4.400 543.640 1296.000 545.040 ;
        RECT 3.990 521.240 1296.000 543.640 ;
        RECT 4.400 519.840 1296.000 521.240 ;
        RECT 3.990 494.040 1296.000 519.840 ;
        RECT 4.400 492.640 1296.000 494.040 ;
        RECT 3.990 490.640 1296.000 492.640 ;
        RECT 4.400 489.240 1296.000 490.640 ;
        RECT 3.990 487.240 1296.000 489.240 ;
        RECT 4.400 485.840 1296.000 487.240 ;
        RECT 3.990 483.840 1296.000 485.840 ;
        RECT 4.400 482.440 1296.000 483.840 ;
        RECT 3.990 477.040 1296.000 482.440 ;
        RECT 4.400 475.640 1296.000 477.040 ;
        RECT 3.990 473.640 1296.000 475.640 ;
        RECT 4.400 472.240 1296.000 473.640 ;
        RECT 3.990 470.240 1296.000 472.240 ;
        RECT 4.400 468.840 1296.000 470.240 ;
        RECT 3.990 466.840 1296.000 468.840 ;
        RECT 4.400 465.440 1296.000 466.840 ;
        RECT 3.990 463.440 1296.000 465.440 ;
        RECT 4.400 462.040 1296.000 463.440 ;
        RECT 3.990 460.040 1296.000 462.040 ;
        RECT 4.400 458.640 1296.000 460.040 ;
        RECT 3.990 456.640 1296.000 458.640 ;
        RECT 4.400 455.240 1296.000 456.640 ;
        RECT 3.990 453.240 1296.000 455.240 ;
        RECT 4.400 451.840 1296.000 453.240 ;
        RECT 3.990 449.840 1296.000 451.840 ;
        RECT 4.400 448.440 1296.000 449.840 ;
        RECT 3.990 446.440 1296.000 448.440 ;
        RECT 4.400 445.040 1296.000 446.440 ;
        RECT 3.990 443.040 1296.000 445.040 ;
        RECT 4.400 441.640 1296.000 443.040 ;
        RECT 3.990 439.640 1296.000 441.640 ;
        RECT 4.400 438.240 1296.000 439.640 ;
        RECT 3.990 426.040 1296.000 438.240 ;
        RECT 4.400 424.640 1296.000 426.040 ;
        RECT 3.990 422.640 1296.000 424.640 ;
        RECT 4.400 421.240 1296.000 422.640 ;
        RECT 3.990 419.240 1296.000 421.240 ;
        RECT 4.400 417.840 1296.000 419.240 ;
        RECT 3.990 402.240 1296.000 417.840 ;
        RECT 4.400 400.840 1296.000 402.240 ;
        RECT 3.990 398.840 1296.000 400.840 ;
        RECT 4.400 397.440 1296.000 398.840 ;
        RECT 3.990 395.440 1296.000 397.440 ;
        RECT 4.400 394.040 1296.000 395.440 ;
        RECT 3.990 392.040 1296.000 394.040 ;
        RECT 4.400 390.640 1296.000 392.040 ;
        RECT 3.990 388.640 1296.000 390.640 ;
        RECT 4.400 387.240 1296.000 388.640 ;
        RECT 3.990 385.240 1296.000 387.240 ;
        RECT 4.400 383.840 1296.000 385.240 ;
        RECT 3.990 381.840 1296.000 383.840 ;
        RECT 4.400 380.440 1296.000 381.840 ;
        RECT 3.990 378.440 1296.000 380.440 ;
        RECT 4.400 377.040 1296.000 378.440 ;
        RECT 3.990 375.040 1296.000 377.040 ;
        RECT 4.400 373.640 1296.000 375.040 ;
        RECT 3.990 10.715 1296.000 373.640 ;
      LAYER met4 ;
        RECT 23.295 31.455 23.940 1276.865 ;
        RECT 26.340 31.455 174.240 1276.865 ;
        RECT 176.640 31.455 177.540 1276.865 ;
        RECT 179.940 31.455 327.840 1276.865 ;
        RECT 330.240 31.455 331.140 1276.865 ;
        RECT 333.540 31.455 481.440 1276.865 ;
        RECT 483.840 31.455 484.740 1276.865 ;
        RECT 487.140 31.455 635.040 1276.865 ;
        RECT 637.440 31.455 638.340 1276.865 ;
        RECT 640.740 31.455 788.640 1276.865 ;
        RECT 791.040 31.455 791.940 1276.865 ;
        RECT 794.340 31.455 833.225 1276.865 ;
  END
END fft_ctrl_tlul
END LIBRARY

